VERSION 5.4 ;
NAMESCASESENSITIVE ON ;
BUSBITCHARS "[]" ;
DIVIDERCHAR "/" ;
UNITS
  DATABASE MICRONS 2000 ;
END UNITS
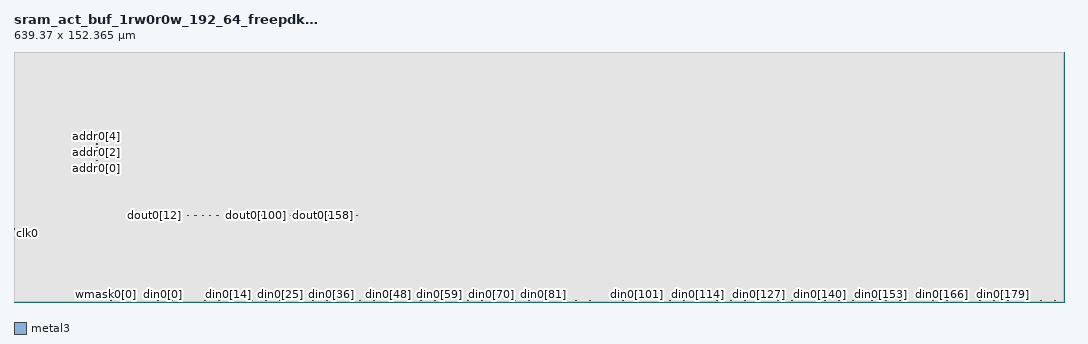
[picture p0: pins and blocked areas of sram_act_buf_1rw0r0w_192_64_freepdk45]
MACRO sram_act_buf_1rw0r0w_192_64_freepdk45
   CLASS BLOCK ;
   SIZE 639.37 BY 152.365 ;
   SYMMETRY X Y R90 ;
   PIN din0[0]
      DIRECTION INPUT ;
      PORT
         LAYER metal3 ;
         RECT  90.465 1.04 90.6 1.175 ;
      END
   END din0[0]
   PIN din0[1]
      DIRECTION INPUT ;
      PORT
         LAYER metal3 ;
         RECT  93.325 1.04 93.46 1.175 ;
      END
   END din0[1]
   PIN din0[2]
      DIRECTION INPUT ;
      PORT
         LAYER metal3 ;
         RECT  96.185 1.04 96.32 1.175 ;
      END
   END din0[2]
   PIN din0[3]
      DIRECTION INPUT ;
      PORT
         LAYER metal3 ;
         RECT  99.045 1.04 99.18 1.175 ;
      END
   END din0[3]
   PIN din0[4]
      DIRECTION INPUT ;
      PORT
         LAYER metal3 ;
         RECT  101.905 1.04 102.04 1.175 ;
      END
   END din0[4]
   PIN din0[5]
      DIRECTION INPUT ;
      PORT
         LAYER metal3 ;
         RECT  104.765 1.04 104.9 1.175 ;
      END
   END din0[5]
   PIN din0[6]
      DIRECTION INPUT ;
      PORT
         LAYER metal3 ;
         RECT  107.625 1.04 107.76 1.175 ;
      END
   END din0[6]
   PIN din0[7]
      DIRECTION INPUT ;
      PORT
         LAYER metal3 ;
         RECT  110.485 1.04 110.62 1.175 ;
      END
   END din0[7]
   PIN din0[8]
      DIRECTION INPUT ;
      PORT
         LAYER metal3 ;
         RECT  113.345 1.04 113.48 1.175 ;
      END
   END din0[8]
   PIN din0[9]
      DIRECTION INPUT ;
      PORT
         LAYER metal3 ;
         RECT  116.205 1.04 116.34 1.175 ;
      END
   END din0[9]
   PIN din0[10]
      DIRECTION INPUT ;
      PORT
         LAYER metal3 ;
         RECT  119.065 1.04 119.2 1.175 ;
      END
   END din0[10]
   PIN din0[11]
      DIRECTION INPUT ;
      PORT
         LAYER metal3 ;
         RECT  121.925 1.04 122.06 1.175 ;
      END
   END din0[11]
   PIN din0[12]
      DIRECTION INPUT ;
      PORT
         LAYER metal3 ;
         RECT  124.785 1.04 124.92 1.175 ;
      END
   END din0[12]
   PIN din0[13]
      DIRECTION INPUT ;
      PORT
         LAYER metal3 ;
         RECT  127.645 1.04 127.78 1.175 ;
      END
   END din0[13]
   PIN din0[14]
      DIRECTION INPUT ;
      PORT
         LAYER metal3 ;
         RECT  130.505 1.04 130.64 1.175 ;
      END
   END din0[14]
   PIN din0[15]
      DIRECTION INPUT ;
      PORT
         LAYER metal3 ;
         RECT  133.365 1.04 133.5 1.175 ;
      END
   END din0[15]
   PIN din0[16]
      DIRECTION INPUT ;
      PORT
         LAYER metal3 ;
         RECT  136.225 1.04 136.36 1.175 ;
      END
   END din0[16]
   PIN din0[17]
      DIRECTION INPUT ;
      PORT
         LAYER metal3 ;
         RECT  139.085 1.04 139.22 1.175 ;
      END
   END din0[17]
   PIN din0[18]
      DIRECTION INPUT ;
      PORT
         LAYER metal3 ;
         RECT  141.945 1.04 142.08 1.175 ;
      END
   END din0[18]
   PIN din0[19]
      DIRECTION INPUT ;
      PORT
         LAYER metal3 ;
         RECT  144.805 1.04 144.94 1.175 ;
      END
   END din0[19]
   PIN din0[20]
      DIRECTION INPUT ;
      PORT
         LAYER metal3 ;
         RECT  147.665 1.04 147.8 1.175 ;
      END
   END din0[20]
   PIN din0[21]
      DIRECTION INPUT ;
      PORT
         LAYER metal3 ;
         RECT  150.525 1.04 150.66 1.175 ;
      END
   END din0[21]
   PIN din0[22]
      DIRECTION INPUT ;
      PORT
         LAYER metal3 ;
         RECT  153.385 1.04 153.52 1.175 ;
      END
   END din0[22]
   PIN din0[23]
      DIRECTION INPUT ;
      PORT
         LAYER metal3 ;
         RECT  156.245 1.04 156.38 1.175 ;
      END
   END din0[23]
   PIN din0[24]
      DIRECTION INPUT ;
      PORT
         LAYER metal3 ;
         RECT  159.105 1.04 159.24 1.175 ;
      END
   END din0[24]
   PIN din0[25]
      DIRECTION INPUT ;
      PORT
         LAYER metal3 ;
         RECT  161.965 1.04 162.1 1.175 ;
      END
   END din0[25]
   PIN din0[26]
      DIRECTION INPUT ;
      PORT
         LAYER metal3 ;
         RECT  164.825 1.04 164.96 1.175 ;
      END
   END din0[26]
   PIN din0[27]
      DIRECTION INPUT ;
      PORT
         LAYER metal3 ;
         RECT  167.685 1.04 167.82 1.175 ;
      END
   END din0[27]
   PIN din0[28]
      DIRECTION INPUT ;
      PORT
         LAYER metal3 ;
         RECT  170.545 1.04 170.68 1.175 ;
      END
   END din0[28]
   PIN din0[29]
      DIRECTION INPUT ;
      PORT
         LAYER metal3 ;
         RECT  173.405 1.04 173.54 1.175 ;
      END
   END din0[29]
   PIN din0[30]
      DIRECTION INPUT ;
      PORT
         LAYER metal3 ;
         RECT  176.265 1.04 176.4 1.175 ;
      END
   END din0[30]
   PIN din0[31]
      DIRECTION INPUT ;
      PORT
         LAYER metal3 ;
         RECT  179.125 1.04 179.26 1.175 ;
      END
   END din0[31]
   PIN din0[32]
      DIRECTION INPUT ;
      PORT
         LAYER metal3 ;
         RECT  181.985 1.04 182.12 1.175 ;
      END
   END din0[32]
   PIN din0[33]
      DIRECTION INPUT ;
      PORT
         LAYER metal3 ;
         RECT  184.845 1.04 184.98 1.175 ;
      END
   END din0[33]
   PIN din0[34]
      DIRECTION INPUT ;
      PORT
         LAYER metal3 ;
         RECT  187.705 1.04 187.84 1.175 ;
      END
   END din0[34]
   PIN din0[35]
      DIRECTION INPUT ;
      PORT
         LAYER metal3 ;
         RECT  190.565 1.04 190.7 1.175 ;
      END
   END din0[35]
   PIN din0[36]
      DIRECTION INPUT ;
      PORT
         LAYER metal3 ;
         RECT  193.425 1.04 193.56 1.175 ;
      END
   END din0[36]
   PIN din0[37]
      DIRECTION INPUT ;
      PORT
         LAYER metal3 ;
         RECT  196.285 1.04 196.42 1.175 ;
      END
   END din0[37]
   PIN din0[38]
      DIRECTION INPUT ;
      PORT
         LAYER metal3 ;
         RECT  199.145 1.04 199.28 1.175 ;
      END
   END din0[38]
   PIN din0[39]
      DIRECTION INPUT ;
      PORT
         LAYER metal3 ;
         RECT  202.005 1.04 202.14 1.175 ;
      END
   END din0[39]
   PIN din0[40]
      DIRECTION INPUT ;
      PORT
         LAYER metal3 ;
         RECT  204.865 1.04 205 1.175 ;
      END
   END din0[40]
   PIN din0[41]
      DIRECTION INPUT ;
      PORT
         LAYER metal3 ;
         RECT  207.725 1.04 207.86 1.175 ;
      END
   END din0[41]
   PIN din0[42]
      DIRECTION INPUT ;
      PORT
         LAYER metal3 ;
         RECT  210.585 1.04 210.72 1.175 ;
      END
   END din0[42]
   PIN din0[43]
      DIRECTION INPUT ;
      PORT
         LAYER metal3 ;
         RECT  213.445 1.04 213.58 1.175 ;
      END
   END din0[43]
   PIN din0[44]
      DIRECTION INPUT ;
      PORT
         LAYER metal3 ;
         RECT  216.305 1.04 216.44 1.175 ;
      END
   END din0[44]
   PIN din0[45]
      DIRECTION INPUT ;
      PORT
         LAYER metal3 ;
         RECT  219.165 1.04 219.3 1.175 ;
      END
   END din0[45]
   PIN din0[46]
      DIRECTION INPUT ;
      PORT
         LAYER metal3 ;
         RECT  222.025 1.04 222.16 1.175 ;
      END
   END din0[46]
   PIN din0[47]
      DIRECTION INPUT ;
      PORT
         LAYER metal3 ;
         RECT  224.885 1.04 225.02 1.175 ;
      END
   END din0[47]
   PIN din0[48]
      DIRECTION INPUT ;
      PORT
         LAYER metal3 ;
         RECT  227.745 1.04 227.88 1.175 ;
      END
   END din0[48]
   PIN din0[49]
      DIRECTION INPUT ;
      PORT
         LAYER metal3 ;
         RECT  230.605 1.04 230.74 1.175 ;
      END
   END din0[49]
   PIN din0[50]
      DIRECTION INPUT ;
      PORT
         LAYER metal3 ;
         RECT  233.465 1.04 233.6 1.175 ;
      END
   END din0[50]
   PIN din0[51]
      DIRECTION INPUT ;
      PORT
         LAYER metal3 ;
         RECT  236.325 1.04 236.46 1.175 ;
      END
   END din0[51]
   PIN din0[52]
      DIRECTION INPUT ;
      PORT
         LAYER metal3 ;
         RECT  239.185 1.04 239.32 1.175 ;
      END
   END din0[52]
   PIN din0[53]
      DIRECTION INPUT ;
      PORT
         LAYER metal3 ;
         RECT  242.045 1.04 242.18 1.175 ;
      END
   END din0[53]
   PIN din0[54]
      DIRECTION INPUT ;
      PORT
         LAYER metal3 ;
         RECT  244.905 1.04 245.04 1.175 ;
      END
   END din0[54]
   PIN din0[55]
      DIRECTION INPUT ;
      PORT
         LAYER metal3 ;
         RECT  247.765 1.04 247.9 1.175 ;
      END
   END din0[55]
   PIN din0[56]
      DIRECTION INPUT ;
      PORT
         LAYER metal3 ;
         RECT  250.625 1.04 250.76 1.175 ;
      END
   END din0[56]
   PIN din0[57]
      DIRECTION INPUT ;
      PORT
         LAYER metal3 ;
         RECT  253.485 1.04 253.62 1.175 ;
      END
   END din0[57]
   PIN din0[58]
      DIRECTION INPUT ;
      PORT
         LAYER metal3 ;
         RECT  256.345 1.04 256.48 1.175 ;
      END
   END din0[58]
   PIN din0[59]
      DIRECTION INPUT ;
      PORT
         LAYER metal3 ;
         RECT  259.205 1.04 259.34 1.175 ;
      END
   END din0[59]
   PIN din0[60]
      DIRECTION INPUT ;
      PORT
         LAYER metal3 ;
         RECT  262.065 1.04 262.2 1.175 ;
      END
   END din0[60]
   PIN din0[61]
      DIRECTION INPUT ;
      PORT
         LAYER metal3 ;
         RECT  264.925 1.04 265.06 1.175 ;
      END
   END din0[61]
   PIN din0[62]
      DIRECTION INPUT ;
      PORT
         LAYER metal3 ;
         RECT  267.785 1.04 267.92 1.175 ;
      END
   END din0[62]
   PIN din0[63]
      DIRECTION INPUT ;
      PORT
         LAYER metal3 ;
         RECT  270.645 1.04 270.78 1.175 ;
      END
   END din0[63]
   PIN din0[64]
      DIRECTION INPUT ;
      PORT
         LAYER metal3 ;
         RECT  273.505 1.04 273.64 1.175 ;
      END
   END din0[64]
   PIN din0[65]
      DIRECTION INPUT ;
      PORT
         LAYER metal3 ;
         RECT  276.365 1.04 276.5 1.175 ;
      END
   END din0[65]
   PIN din0[66]
      DIRECTION INPUT ;
      PORT
         LAYER metal3 ;
         RECT  279.225 1.04 279.36 1.175 ;
      END
   END din0[66]
   PIN din0[67]
      DIRECTION INPUT ;
      PORT
         LAYER metal3 ;
         RECT  282.085 1.04 282.22 1.175 ;
      END
   END din0[67]
   PIN din0[68]
      DIRECTION INPUT ;
      PORT
         LAYER metal3 ;
         RECT  284.945 1.04 285.08 1.175 ;
      END
   END din0[68]
   PIN din0[69]
      DIRECTION INPUT ;
      PORT
         LAYER metal3 ;
         RECT  287.805 1.04 287.94 1.175 ;
      END
   END din0[69]
   PIN din0[70]
      DIRECTION INPUT ;
      PORT
         LAYER metal3 ;
         RECT  290.665 1.04 290.8 1.175 ;
      END
   END din0[70]
   PIN din0[71]
      DIRECTION INPUT ;
      PORT
         LAYER metal3 ;
         RECT  293.525 1.04 293.66 1.175 ;
      END
   END din0[71]
   PIN din0[72]
      DIRECTION INPUT ;
      PORT
         LAYER metal3 ;
         RECT  296.385 1.04 296.52 1.175 ;
      END
   END din0[72]
   PIN din0[73]
      DIRECTION INPUT ;
      PORT
         LAYER metal3 ;
         RECT  299.245 1.04 299.38 1.175 ;
      END
   END din0[73]
   PIN din0[74]
      DIRECTION INPUT ;
      PORT
         LAYER metal3 ;
         RECT  302.105 1.04 302.24 1.175 ;
      END
   END din0[74]
   PIN din0[75]
      DIRECTION INPUT ;
      PORT
         LAYER metal3 ;
         RECT  304.965 1.04 305.1 1.175 ;
      END
   END din0[75]
   PIN din0[76]
      DIRECTION INPUT ;
      PORT
         LAYER metal3 ;
         RECT  307.825 1.04 307.96 1.175 ;
      END
   END din0[76]
   PIN din0[77]
      DIRECTION INPUT ;
      PORT
         LAYER metal3 ;
         RECT  310.685 1.04 310.82 1.175 ;
      END
   END din0[77]
   PIN din0[78]
      DIRECTION INPUT ;
      PORT
         LAYER metal3 ;
         RECT  313.545 1.04 313.68 1.175 ;
      END
   END din0[78]
   PIN din0[79]
      DIRECTION INPUT ;
      PORT
         LAYER metal3 ;
         RECT  316.405 1.04 316.54 1.175 ;
      END
   END din0[79]
   PIN din0[80]
      DIRECTION INPUT ;
      PORT
         LAYER metal3 ;
         RECT  319.265 1.04 319.4 1.175 ;
      END
   END din0[80]
   PIN din0[81]
      DIRECTION INPUT ;
      PORT
         LAYER metal3 ;
         RECT  322.125 1.04 322.26 1.175 ;
      END
   END din0[81]
   PIN din0[82]
      DIRECTION INPUT ;
      PORT
         LAYER metal3 ;
         RECT  324.985 1.04 325.12 1.175 ;
      END
   END din0[82]
   PIN din0[83]
      DIRECTION INPUT ;
      PORT
         LAYER metal3 ;
         RECT  327.845 1.04 327.98 1.175 ;
      END
   END din0[83]
   PIN din0[84]
      DIRECTION INPUT ;
      PORT
         LAYER metal3 ;
         RECT  330.705 1.04 330.84 1.175 ;
      END
   END din0[84]
   PIN din0[85]
      DIRECTION INPUT ;
      PORT
         LAYER metal3 ;
         RECT  333.565 1.04 333.7 1.175 ;
      END
   END din0[85]
   PIN din0[86]
      DIRECTION INPUT ;
      PORT
         LAYER metal3 ;
         RECT  336.425 1.04 336.56 1.175 ;
      END
   END din0[86]
   PIN din0[87]
      DIRECTION INPUT ;
      PORT
         LAYER metal3 ;
         RECT  339.285 1.04 339.42 1.175 ;
      END
   END din0[87]
   PIN din0[88]
      DIRECTION INPUT ;
      PORT
         LAYER metal3 ;
         RECT  342.145 1.04 342.28 1.175 ;
      END
   END din0[88]
   PIN din0[89]
      DIRECTION INPUT ;
      PORT
         LAYER metal3 ;
         RECT  345.005 1.04 345.14 1.175 ;
      END
   END din0[89]
   PIN din0[90]
      DIRECTION INPUT ;
      PORT
         LAYER metal3 ;
         RECT  347.865 1.04 348 1.175 ;
      END
   END din0[90]
   PIN din0[91]
      DIRECTION INPUT ;
      PORT
         LAYER metal3 ;
         RECT  350.725 1.04 350.86 1.175 ;
      END
   END din0[91]
   PIN din0[92]
      DIRECTION INPUT ;
      PORT
         LAYER metal3 ;
         RECT  353.585 1.04 353.72 1.175 ;
      END
   END din0[92]
   PIN din0[93]
      DIRECTION INPUT ;
      PORT
         LAYER metal3 ;
         RECT  356.445 1.04 356.58 1.175 ;
      END
   END din0[93]
   PIN din0[94]
      DIRECTION INPUT ;
      PORT
         LAYER metal3 ;
         RECT  359.305 1.04 359.44 1.175 ;
      END
   END din0[94]
   PIN din0[95]
      DIRECTION INPUT ;
      PORT
         LAYER metal3 ;
         RECT  362.165 1.04 362.3 1.175 ;
      END
   END din0[95]
   PIN din0[96]
      DIRECTION INPUT ;
      PORT
         LAYER metal3 ;
         RECT  365.025 1.04 365.16 1.175 ;
      END
   END din0[96]
   PIN din0[97]
      DIRECTION INPUT ;
      PORT
         LAYER metal3 ;
         RECT  367.885 1.04 368.02 1.175 ;
      END
   END din0[97]
   PIN din0[98]
      DIRECTION INPUT ;
      PORT
         LAYER metal3 ;
         RECT  370.745 1.04 370.88 1.175 ;
      END
   END din0[98]
   PIN din0[99]
      DIRECTION INPUT ;
      PORT
         LAYER metal3 ;
         RECT  373.605 1.04 373.74 1.175 ;
      END
   END din0[99]
   PIN din0[100]
      DIRECTION INPUT ;
      PORT
         LAYER metal3 ;
         RECT  376.465 1.04 376.6 1.175 ;
      END
   END din0[100]
   PIN din0[101]
      DIRECTION INPUT ;
      PORT
         LAYER metal3 ;
         RECT  379.325 1.04 379.46 1.175 ;
      END
   END din0[101]
   PIN din0[102]
      DIRECTION INPUT ;
      PORT
         LAYER metal3 ;
         RECT  382.185 1.04 382.32 1.175 ;
      END
   END din0[102]
   PIN din0[103]
      DIRECTION INPUT ;
      PORT
         LAYER metal3 ;
         RECT  385.045 1.04 385.18 1.175 ;
      END
   END din0[103]
   PIN din0[104]
      DIRECTION INPUT ;
      PORT
         LAYER metal3 ;
         RECT  387.905 1.04 388.04 1.175 ;
      END
   END din0[104]
   PIN din0[105]
      DIRECTION INPUT ;
      PORT
         LAYER metal3 ;
         RECT  390.765 1.04 390.9 1.175 ;
      END
   END din0[105]
   PIN din0[106]
      DIRECTION INPUT ;
      PORT
         LAYER metal3 ;
         RECT  393.625 1.04 393.76 1.175 ;
      END
   END din0[106]
   PIN din0[107]
      DIRECTION INPUT ;
      PORT
         LAYER metal3 ;
         RECT  396.485 1.04 396.62 1.175 ;
      END
   END din0[107]
   PIN din0[108]
      DIRECTION INPUT ;
      PORT
         LAYER metal3 ;
         RECT  399.345 1.04 399.48 1.175 ;
      END
   END din0[108]
   PIN din0[109]
      DIRECTION INPUT ;
      PORT
         LAYER metal3 ;
         RECT  402.205 1.04 402.34 1.175 ;
      END
   END din0[109]
   PIN din0[110]
      DIRECTION INPUT ;
      PORT
         LAYER metal3 ;
         RECT  405.065 1.04 405.2 1.175 ;
      END
   END din0[110]
   PIN din0[111]
      DIRECTION INPUT ;
      PORT
         LAYER metal3 ;
         RECT  407.925 1.04 408.06 1.175 ;
      END
   END din0[111]
   PIN din0[112]
      DIRECTION INPUT ;
      PORT
         LAYER metal3 ;
         RECT  410.785 1.04 410.92 1.175 ;
      END
   END din0[112]
   PIN din0[113]
      DIRECTION INPUT ;
      PORT
         LAYER metal3 ;
         RECT  413.645 1.04 413.78 1.175 ;
      END
   END din0[113]
   PIN din0[114]
      DIRECTION INPUT ;
      PORT
         LAYER metal3 ;
         RECT  416.505 1.04 416.64 1.175 ;
      END
   END din0[114]
   PIN din0[115]
      DIRECTION INPUT ;
      PORT
         LAYER metal3 ;
         RECT  419.365 1.04 419.5 1.175 ;
      END
   END din0[115]
   PIN din0[116]
      DIRECTION INPUT ;
      PORT
         LAYER metal3 ;
         RECT  422.225 1.04 422.36 1.175 ;
      END
   END din0[116]
   PIN din0[117]
      DIRECTION INPUT ;
      PORT
         LAYER metal3 ;
         RECT  425.085 1.04 425.22 1.175 ;
      END
   END din0[117]
   PIN din0[118]
      DIRECTION INPUT ;
      PORT
         LAYER metal3 ;
         RECT  427.945 1.04 428.08 1.175 ;
      END
   END din0[118]
   PIN din0[119]
      DIRECTION INPUT ;
      PORT
         LAYER metal3 ;
         RECT  430.805 1.04 430.94 1.175 ;
      END
   END din0[119]
   PIN din0[120]
      DIRECTION INPUT ;
      PORT
         LAYER metal3 ;
         RECT  433.665 1.04 433.8 1.175 ;
      END
   END din0[120]
   PIN din0[121]
      DIRECTION INPUT ;
      PORT
         LAYER metal3 ;
         RECT  436.525 1.04 436.66 1.175 ;
      END
   END din0[121]
   PIN din0[122]
      DIRECTION INPUT ;
      PORT
         LAYER metal3 ;
         RECT  439.385 1.04 439.52 1.175 ;
      END
   END din0[122]
   PIN din0[123]
      DIRECTION INPUT ;
      PORT
         LAYER metal3 ;
         RECT  442.245 1.04 442.38 1.175 ;
      END
   END din0[123]
   PIN din0[124]
      DIRECTION INPUT ;
      PORT
         LAYER metal3 ;
         RECT  445.105 1.04 445.24 1.175 ;
      END
   END din0[124]
   PIN din0[125]
      DIRECTION INPUT ;
      PORT
         LAYER metal3 ;
         RECT  447.965 1.04 448.1 1.175 ;
      END
   END din0[125]
   PIN din0[126]
      DIRECTION INPUT ;
      PORT
         LAYER metal3 ;
         RECT  450.825 1.04 450.96 1.175 ;
      END
   END din0[126]
   PIN din0[127]
      DIRECTION INPUT ;
      PORT
         LAYER metal3 ;
         RECT  453.685 1.04 453.82 1.175 ;
      END
   END din0[127]
   PIN din0[128]
      DIRECTION INPUT ;
      PORT
         LAYER metal3 ;
         RECT  456.545 1.04 456.68 1.175 ;
      END
   END din0[128]
   PIN din0[129]
      DIRECTION INPUT ;
      PORT
         LAYER metal3 ;
         RECT  459.405 1.04 459.54 1.175 ;
      END
   END din0[129]
   PIN din0[130]
      DIRECTION INPUT ;
      PORT
         LAYER metal3 ;
         RECT  462.265 1.04 462.4 1.175 ;
      END
   END din0[130]
   PIN din0[131]
      DIRECTION INPUT ;
      PORT
         LAYER metal3 ;
         RECT  465.125 1.04 465.26 1.175 ;
      END
   END din0[131]
   PIN din0[132]
      DIRECTION INPUT ;
      PORT
         LAYER metal3 ;
         RECT  467.985 1.04 468.12 1.175 ;
      END
   END din0[132]
   PIN din0[133]
      DIRECTION INPUT ;
      PORT
         LAYER metal3 ;
         RECT  470.845 1.04 470.98 1.175 ;
      END
   END din0[133]
   PIN din0[134]
      DIRECTION INPUT ;
      PORT
         LAYER metal3 ;
         RECT  473.705 1.04 473.84 1.175 ;
      END
   END din0[134]
   PIN din0[135]
      DIRECTION INPUT ;
      PORT
         LAYER metal3 ;
         RECT  476.565 1.04 476.7 1.175 ;
      END
   END din0[135]
   PIN din0[136]
      DIRECTION INPUT ;
      PORT
         LAYER metal3 ;
         RECT  479.425 1.04 479.56 1.175 ;
      END
   END din0[136]
   PIN din0[137]
      DIRECTION INPUT ;
      PORT
         LAYER metal3 ;
         RECT  482.285 1.04 482.42 1.175 ;
      END
   END din0[137]
   PIN din0[138]
      DIRECTION INPUT ;
      PORT
         LAYER metal3 ;
         RECT  485.145 1.04 485.28 1.175 ;
      END
   END din0[138]
   PIN din0[139]
      DIRECTION INPUT ;
      PORT
         LAYER metal3 ;
         RECT  488.005 1.04 488.14 1.175 ;
      END
   END din0[139]
   PIN din0[140]
      DIRECTION INPUT ;
      PORT
         LAYER metal3 ;
         RECT  490.865 1.04 491 1.175 ;
      END
   END din0[140]
   PIN din0[141]
      DIRECTION INPUT ;
      PORT
         LAYER metal3 ;
         RECT  493.725 1.04 493.86 1.175 ;
      END
   END din0[141]
   PIN din0[142]
      DIRECTION INPUT ;
      PORT
         LAYER metal3 ;
         RECT  496.585 1.04 496.72 1.175 ;
      END
   END din0[142]
   PIN din0[143]
      DIRECTION INPUT ;
      PORT
         LAYER metal3 ;
         RECT  499.445 1.04 499.58 1.175 ;
      END
   END din0[143]
   PIN din0[144]
      DIRECTION INPUT ;
      PORT
         LAYER metal3 ;
         RECT  502.305 1.04 502.44 1.175 ;
      END
   END din0[144]
   PIN din0[145]
      DIRECTION INPUT ;
      PORT
         LAYER metal3 ;
         RECT  505.165 1.04 505.3 1.175 ;
      END
   END din0[145]
   PIN din0[146]
      DIRECTION INPUT ;
      PORT
         LAYER metal3 ;
         RECT  508.025 1.04 508.16 1.175 ;
      END
   END din0[146]
   PIN din0[147]
      DIRECTION INPUT ;
      PORT
         LAYER metal3 ;
         RECT  510.885 1.04 511.02 1.175 ;
      END
   END din0[147]
   PIN din0[148]
      DIRECTION INPUT ;
      PORT
         LAYER metal3 ;
         RECT  513.745 1.04 513.88 1.175 ;
      END
   END din0[148]
   PIN din0[149]
      DIRECTION INPUT ;
      PORT
         LAYER metal3 ;
         RECT  516.605 1.04 516.74 1.175 ;
      END
   END din0[149]
   PIN din0[150]
      DIRECTION INPUT ;
      PORT
         LAYER metal3 ;
         RECT  519.465 1.04 519.6 1.175 ;
      END
   END din0[150]
   PIN din0[151]
      DIRECTION INPUT ;
      PORT
         LAYER metal3 ;
         RECT  522.325 1.04 522.46 1.175 ;
      END
   END din0[151]
   PIN din0[152]
      DIRECTION INPUT ;
      PORT
         LAYER metal3 ;
         RECT  525.185 1.04 525.32 1.175 ;
      END
   END din0[152]
   PIN din0[153]
      DIRECTION INPUT ;
      PORT
         LAYER metal3 ;
         RECT  528.045 1.04 528.18 1.175 ;
      END
   END din0[153]
   PIN din0[154]
      DIRECTION INPUT ;
      PORT
         LAYER metal3 ;
         RECT  530.905 1.04 531.04 1.175 ;
      END
   END din0[154]
   PIN din0[155]
      DIRECTION INPUT ;
      PORT
         LAYER metal3 ;
         RECT  533.765 1.04 533.9 1.175 ;
      END
   END din0[155]
   PIN din0[156]
      DIRECTION INPUT ;
      PORT
         LAYER metal3 ;
         RECT  536.625 1.04 536.76 1.175 ;
      END
   END din0[156]
   PIN din0[157]
      DIRECTION INPUT ;
      PORT
         LAYER metal3 ;
         RECT  539.485 1.04 539.62 1.175 ;
      END
   END din0[157]
   PIN din0[158]
      DIRECTION INPUT ;
      PORT
         LAYER metal3 ;
         RECT  542.345 1.04 542.48 1.175 ;
      END
   END din0[158]
   PIN din0[159]
      DIRECTION INPUT ;
      PORT
         LAYER metal3 ;
         RECT  545.205 1.04 545.34 1.175 ;
      END
   END din0[159]
   PIN din0[160]
      DIRECTION INPUT ;
      PORT
         LAYER metal3 ;
         RECT  548.065 1.04 548.2 1.175 ;
      END
   END din0[160]
   PIN din0[161]
      DIRECTION INPUT ;
      PORT
         LAYER metal3 ;
         RECT  550.925 1.04 551.06 1.175 ;
      END
   END din0[161]
   PIN din0[162]
      DIRECTION INPUT ;
      PORT
         LAYER metal3 ;
         RECT  553.785 1.04 553.92 1.175 ;
      END
   END din0[162]
   PIN din0[163]
      DIRECTION INPUT ;
      PORT
         LAYER metal3 ;
         RECT  556.645 1.04 556.78 1.175 ;
      END
   END din0[163]
   PIN din0[164]
      DIRECTION INPUT ;
      PORT
         LAYER metal3 ;
         RECT  559.505 1.04 559.64 1.175 ;
      END
   END din0[164]
   PIN din0[165]
      DIRECTION INPUT ;
      PORT
         LAYER metal3 ;
         RECT  562.365 1.04 562.5 1.175 ;
      END
   END din0[165]
   PIN din0[166]
      DIRECTION INPUT ;
      PORT
         LAYER metal3 ;
         RECT  565.225 1.04 565.36 1.175 ;
      END
   END din0[166]
   PIN din0[167]
      DIRECTION INPUT ;
      PORT
         LAYER metal3 ;
         RECT  568.085 1.04 568.22 1.175 ;
      END
   END din0[167]
   PIN din0[168]
      DIRECTION INPUT ;
      PORT
         LAYER metal3 ;
         RECT  570.945 1.04 571.08 1.175 ;
      END
   END din0[168]
   PIN din0[169]
      DIRECTION INPUT ;
      PORT
         LAYER metal3 ;
         RECT  573.805 1.04 573.94 1.175 ;
      END
   END din0[169]
   PIN din0[170]
      DIRECTION INPUT ;
      PORT
         LAYER metal3 ;
         RECT  576.665 1.04 576.8 1.175 ;
      END
   END din0[170]
   PIN din0[171]
      DIRECTION INPUT ;
      PORT
         LAYER metal3 ;
         RECT  579.525 1.04 579.66 1.175 ;
      END
   END din0[171]
   PIN din0[172]
      DIRECTION INPUT ;
      PORT
         LAYER metal3 ;
         RECT  582.385 1.04 582.52 1.175 ;
      END
   END din0[172]
   PIN din0[173]
      DIRECTION INPUT ;
      PORT
         LAYER metal3 ;
         RECT  585.245 1.04 585.38 1.175 ;
      END
   END din0[173]
   PIN din0[174]
      DIRECTION INPUT ;
      PORT
         LAYER metal3 ;
         RECT  588.105 1.04 588.24 1.175 ;
      END
   END din0[174]
   PIN din0[175]
      DIRECTION INPUT ;
      PORT
         LAYER metal3 ;
         RECT  590.965 1.04 591.1 1.175 ;
      END
   END din0[175]
   PIN din0[176]
      DIRECTION INPUT ;
      PORT
         LAYER metal3 ;
         RECT  593.825 1.04 593.96 1.175 ;
      END
   END din0[176]
   PIN din0[177]
      DIRECTION INPUT ;
      PORT
         LAYER metal3 ;
         RECT  596.685 1.04 596.82 1.175 ;
      END
   END din0[177]
   PIN din0[178]
      DIRECTION INPUT ;
      PORT
         LAYER metal3 ;
         RECT  599.545 1.04 599.68 1.175 ;
      END
   END din0[178]
   PIN din0[179]
      DIRECTION INPUT ;
      PORT
         LAYER metal3 ;
         RECT  602.405 1.04 602.54 1.175 ;
      END
   END din0[179]
   PIN din0[180]
      DIRECTION INPUT ;
      PORT
         LAYER metal3 ;
         RECT  605.265 1.04 605.4 1.175 ;
      END
   END din0[180]
   PIN din0[181]
      DIRECTION INPUT ;
      PORT
         LAYER metal3 ;
         RECT  608.125 1.04 608.26 1.175 ;
      END
   END din0[181]
   PIN din0[182]
      DIRECTION INPUT ;
      PORT
         LAYER metal3 ;
         RECT  610.985 1.04 611.12 1.175 ;
      END
   END din0[182]
   PIN din0[183]
      DIRECTION INPUT ;
      PORT
         LAYER metal3 ;
         RECT  613.845 1.04 613.98 1.175 ;
      END
   END din0[183]
   PIN din0[184]
      DIRECTION INPUT ;
      PORT
         LAYER metal3 ;
         RECT  616.705 1.04 616.84 1.175 ;
      END
   END din0[184]
   PIN din0[185]
      DIRECTION INPUT ;
      PORT
         LAYER metal3 ;
         RECT  619.565 1.04 619.7 1.175 ;
      END
   END din0[185]
   PIN din0[186]
      DIRECTION INPUT ;
      PORT
         LAYER metal3 ;
         RECT  622.425 1.04 622.56 1.175 ;
      END
   END din0[186]
   PIN din0[187]
      DIRECTION INPUT ;
      PORT
         LAYER metal3 ;
         RECT  625.285 1.04 625.42 1.175 ;
      END
   END din0[187]
   PIN din0[188]
      DIRECTION INPUT ;
      PORT
         LAYER metal3 ;
         RECT  628.145 1.04 628.28 1.175 ;
      END
   END din0[188]
   PIN din0[189]
      DIRECTION INPUT ;
      PORT
         LAYER metal3 ;
         RECT  631.005 1.04 631.14 1.175 ;
      END
   END din0[189]
   PIN din0[190]
      DIRECTION INPUT ;
      PORT
         LAYER metal3 ;
         RECT  633.865 1.04 634 1.175 ;
      END
   END din0[190]
   PIN din0[191]
      DIRECTION INPUT ;
      PORT
         LAYER metal3 ;
         RECT  636.725 1.04 636.86 1.175 ;
      END
   END din0[191]
   PIN addr0[0]
      DIRECTION INPUT ;
      PORT
         LAYER metal3 ;
         RECT  50.425 86.32 50.56 86.455 ;
      END
   END addr0[0]
   PIN addr0[1]
      DIRECTION INPUT ;
      PORT
         LAYER metal3 ;
         RECT  50.425 89.05 50.56 89.185 ;
      END
   END addr0[1]
   PIN addr0[2]
      DIRECTION INPUT ;
      PORT
         LAYER metal3 ;
         RECT  50.425 91.26 50.56 91.395 ;
      END
   END addr0[2]
   PIN addr0[3]
      DIRECTION INPUT ;
      PORT
         LAYER metal3 ;
         RECT  50.425 93.99 50.56 94.125 ;
      END
   END addr0[3]
   PIN addr0[4]
      DIRECTION INPUT ;
      PORT
         LAYER metal3 ;
         RECT  50.425 96.2 50.56 96.335 ;
      END
   END addr0[4]
   PIN addr0[5]
      DIRECTION INPUT ;
      PORT
         LAYER metal3 ;
         RECT  50.425 98.93 50.56 99.065 ;
      END
   END addr0[5]
   PIN csb0
      DIRECTION INPUT ;
      PORT
         LAYER metal3 ;
         RECT  0.285 41.6 0.42 41.735 ;
      END
   END csb0
   PIN web0
      DIRECTION INPUT ;
      PORT
         LAYER metal3 ;
         RECT  0.285 44.33 0.42 44.465 ;
      END
   END web0
   PIN clk0
      DIRECTION INPUT ;
      PORT
         LAYER metal3 ;
         RECT  6.53 41.685 6.66 41.82 ;
      END
   END clk0
   PIN wmask0[0]
      DIRECTION INPUT ;
      PORT
         LAYER metal3 ;
         RECT  56.145 1.04 56.28 1.175 ;
      END
   END wmask0[0]
   PIN wmask0[1]
      DIRECTION INPUT ;
      PORT
         LAYER metal3 ;
         RECT  59.005 1.04 59.14 1.175 ;
      END
   END wmask0[1]
   PIN wmask0[2]
      DIRECTION INPUT ;
      PORT
         LAYER metal3 ;
         RECT  61.865 1.04 62 1.175 ;
      END
   END wmask0[2]
   PIN wmask0[3]
      DIRECTION INPUT ;
      PORT
         LAYER metal3 ;
         RECT  64.725 1.04 64.86 1.175 ;
      END
   END wmask0[3]
   PIN wmask0[4]
      DIRECTION INPUT ;
      PORT
         LAYER metal3 ;
         RECT  67.585 1.04 67.72 1.175 ;
      END
   END wmask0[4]
   PIN wmask0[5]
      DIRECTION INPUT ;
      PORT
         LAYER metal3 ;
         RECT  70.445 1.04 70.58 1.175 ;
      END
   END wmask0[5]
   PIN wmask0[6]
      DIRECTION INPUT ;
      PORT
         LAYER metal3 ;
         RECT  73.305 1.04 73.44 1.175 ;
      END
   END wmask0[6]
   PIN wmask0[7]
      DIRECTION INPUT ;
      PORT
         LAYER metal3 ;
         RECT  76.165 1.04 76.3 1.175 ;
      END
   END wmask0[7]
   PIN wmask0[8]
      DIRECTION INPUT ;
      PORT
         LAYER metal3 ;
         RECT  79.025 1.04 79.16 1.175 ;
      END
   END wmask0[8]
   PIN wmask0[9]
      DIRECTION INPUT ;
      PORT
         LAYER metal3 ;
         RECT  81.885 1.04 82.02 1.175 ;
      END
   END wmask0[9]
   PIN wmask0[10]
      DIRECTION INPUT ;
      PORT
         LAYER metal3 ;
         RECT  84.745 1.04 84.88 1.175 ;
      END
   END wmask0[10]
   PIN wmask0[11]
      DIRECTION INPUT ;
      PORT
         LAYER metal3 ;
         RECT  87.605 1.04 87.74 1.175 ;
      END
   END wmask0[11]
   PIN dout0[0]
      DIRECTION OUTPUT ;
      PORT
         LAYER metal3 ;
         RECT  76.955 52.74 77.09 52.88 ;
      END
   END dout0[0]
   PIN dout0[1]
      DIRECTION OUTPUT ;
      PORT
         LAYER metal3 ;
         RECT  77.66 52.74 77.795 52.88 ;
      END
   END dout0[1]
   PIN dout0[2]
      DIRECTION OUTPUT ;
      PORT
         LAYER metal3 ;
         RECT  78.365 52.74 78.5 52.88 ;
      END
   END dout0[2]
   PIN dout0[3]
      DIRECTION OUTPUT ;
      PORT
         LAYER metal3 ;
         RECT  79.07 52.74 79.205 52.88 ;
      END
   END dout0[3]
   PIN dout0[4]
      DIRECTION OUTPUT ;
      PORT
         LAYER metal3 ;
         RECT  79.775 52.74 79.91 52.88 ;
      END
   END dout0[4]
   PIN dout0[5]
      DIRECTION OUTPUT ;
      PORT
         LAYER metal3 ;
         RECT  80.48 52.74 80.615 52.88 ;
      END
   END dout0[5]
   PIN dout0[6]
      DIRECTION OUTPUT ;
      PORT
         LAYER metal3 ;
         RECT  81.185 52.74 81.32 52.88 ;
      END
   END dout0[6]
   PIN dout0[7]
      DIRECTION OUTPUT ;
      PORT
         LAYER metal3 ;
         RECT  81.89 52.74 82.025 52.88 ;
      END
   END dout0[7]
   PIN dout0[8]
      DIRECTION OUTPUT ;
      PORT
         LAYER metal3 ;
         RECT  82.595 52.74 82.73 52.88 ;
      END
   END dout0[8]
   PIN dout0[9]
      DIRECTION OUTPUT ;
      PORT
         LAYER metal3 ;
         RECT  83.3 52.74 83.435 52.88 ;
      END
   END dout0[9]
   PIN dout0[10]
      DIRECTION OUTPUT ;
      PORT
         LAYER metal3 ;
         RECT  84.005 52.74 84.14 52.88 ;
      END
   END dout0[10]
   PIN dout0[11]
      DIRECTION OUTPUT ;
      PORT
         LAYER metal3 ;
         RECT  84.71 52.74 84.845 52.88 ;
      END
   END dout0[11]
   PIN dout0[12]
      DIRECTION OUTPUT ;
      PORT
         LAYER metal3 ;
         RECT  85.415 52.74 85.55 52.88 ;
      END
   END dout0[12]
   PIN dout0[13]
      DIRECTION OUTPUT ;
      PORT
         LAYER metal3 ;
         RECT  86.12 52.74 86.255 52.88 ;
      END
   END dout0[13]
   PIN dout0[14]
      DIRECTION OUTPUT ;
      PORT
         LAYER metal3 ;
         RECT  86.825 52.74 86.96 52.88 ;
      END
   END dout0[14]
   PIN dout0[15]
      DIRECTION OUTPUT ;
      PORT
         LAYER metal3 ;
         RECT  87.53 52.74 87.665 52.88 ;
      END
   END dout0[15]
   PIN dout0[16]
      DIRECTION OUTPUT ;
      PORT
         LAYER metal3 ;
         RECT  88.235 52.74 88.37 52.88 ;
      END
   END dout0[16]
   PIN dout0[17]
      DIRECTION OUTPUT ;
      PORT
         LAYER metal3 ;
         RECT  88.94 52.74 89.075 52.88 ;
      END
   END dout0[17]
   PIN dout0[18]
      DIRECTION OUTPUT ;
      PORT
         LAYER metal3 ;
         RECT  89.645 52.74 89.78 52.88 ;
      END
   END dout0[18]
   PIN dout0[19]
      DIRECTION OUTPUT ;
      PORT
         LAYER metal3 ;
         RECT  90.35 52.74 90.485 52.88 ;
      END
   END dout0[19]
   PIN dout0[20]
      DIRECTION OUTPUT ;
      PORT
         LAYER metal3 ;
         RECT  91.055 52.74 91.19 52.88 ;
      END
   END dout0[20]
   PIN dout0[21]
      DIRECTION OUTPUT ;
      PORT
         LAYER metal3 ;
         RECT  91.76 52.74 91.895 52.88 ;
      END
   END dout0[21]
   PIN dout0[22]
      DIRECTION OUTPUT ;
      PORT
         LAYER metal3 ;
         RECT  92.465 52.74 92.6 52.88 ;
      END
   END dout0[22]
   PIN dout0[23]
      DIRECTION OUTPUT ;
      PORT
         LAYER metal3 ;
         RECT  93.17 52.74 93.305 52.88 ;
      END
   END dout0[23]
   PIN dout0[24]
      DIRECTION OUTPUT ;
      PORT
         LAYER metal3 ;
         RECT  93.875 52.74 94.01 52.88 ;
      END
   END dout0[24]
   PIN dout0[25]
      DIRECTION OUTPUT ;
      PORT
         LAYER metal3 ;
         RECT  94.58 52.74 94.715 52.88 ;
      END
   END dout0[25]
   PIN dout0[26]
      DIRECTION OUTPUT ;
      PORT
         LAYER metal3 ;
         RECT  95.285 52.74 95.42 52.88 ;
      END
   END dout0[26]
   PIN dout0[27]
      DIRECTION OUTPUT ;
      PORT
         LAYER metal3 ;
         RECT  95.99 52.74 96.125 52.88 ;
      END
   END dout0[27]
   PIN dout0[28]
      DIRECTION OUTPUT ;
      PORT
         LAYER metal3 ;
         RECT  96.695 52.74 96.83 52.88 ;
      END
   END dout0[28]
   PIN dout0[29]
      DIRECTION OUTPUT ;
      PORT
         LAYER metal3 ;
         RECT  97.4 52.74 97.535 52.88 ;
      END
   END dout0[29]
   PIN dout0[30]
      DIRECTION OUTPUT ;
      PORT
         LAYER metal3 ;
         RECT  98.105 52.74 98.24 52.88 ;
      END
   END dout0[30]
   PIN dout0[31]
      DIRECTION OUTPUT ;
      PORT
         LAYER metal3 ;
         RECT  98.81 52.74 98.945 52.88 ;
      END
   END dout0[31]
   PIN dout0[32]
      DIRECTION OUTPUT ;
      PORT
         LAYER metal3 ;
         RECT  99.515 52.74 99.65 52.88 ;
      END
   END dout0[32]
   PIN dout0[33]
      DIRECTION OUTPUT ;
      PORT
         LAYER metal3 ;
         RECT  100.22 52.74 100.355 52.88 ;
      END
   END dout0[33]
   PIN dout0[34]
      DIRECTION OUTPUT ;
      PORT
         LAYER metal3 ;
         RECT  100.925 52.74 101.06 52.88 ;
      END
   END dout0[34]
   PIN dout0[35]
      DIRECTION OUTPUT ;
      PORT
         LAYER metal3 ;
         RECT  101.63 52.74 101.765 52.88 ;
      END
   END dout0[35]
   PIN dout0[36]
      DIRECTION OUTPUT ;
      PORT
         LAYER metal3 ;
         RECT  102.335 52.74 102.47 52.88 ;
      END
   END dout0[36]
   PIN dout0[37]
      DIRECTION OUTPUT ;
      PORT
         LAYER metal3 ;
         RECT  103.04 52.74 103.175 52.88 ;
      END
   END dout0[37]
   PIN dout0[38]
      DIRECTION OUTPUT ;
      PORT
         LAYER metal3 ;
         RECT  103.745 52.74 103.88 52.88 ;
      END
   END dout0[38]
   PIN dout0[39]
      DIRECTION OUTPUT ;
      PORT
         LAYER metal3 ;
         RECT  104.45 52.74 104.585 52.88 ;
      END
   END dout0[39]
   PIN dout0[40]
      DIRECTION OUTPUT ;
      PORT
         LAYER metal3 ;
         RECT  105.155 52.74 105.29 52.88 ;
      END
   END dout0[40]
   PIN dout0[41]
      DIRECTION OUTPUT ;
      PORT
         LAYER metal3 ;
         RECT  105.86 52.74 105.995 52.88 ;
      END
   END dout0[41]
   PIN dout0[42]
      DIRECTION OUTPUT ;
      PORT
         LAYER metal3 ;
         RECT  106.565 52.74 106.7 52.88 ;
      END
   END dout0[42]
   PIN dout0[43]
      DIRECTION OUTPUT ;
      PORT
         LAYER metal3 ;
         RECT  107.27 52.74 107.405 52.88 ;
      END
   END dout0[43]
   PIN dout0[44]
      DIRECTION OUTPUT ;
      PORT
         LAYER metal3 ;
         RECT  107.975 52.74 108.11 52.88 ;
      END
   END dout0[44]
   PIN dout0[45]
      DIRECTION OUTPUT ;
      PORT
         LAYER metal3 ;
         RECT  108.68 52.74 108.815 52.88 ;
      END
   END dout0[45]
   PIN dout0[46]
      DIRECTION OUTPUT ;
      PORT
         LAYER metal3 ;
         RECT  109.385 52.74 109.52 52.88 ;
      END
   END dout0[46]
   PIN dout0[47]
      DIRECTION OUTPUT ;
      PORT
         LAYER metal3 ;
         RECT  110.09 52.74 110.225 52.88 ;
      END
   END dout0[47]
   PIN dout0[48]
      DIRECTION OUTPUT ;
      PORT
         LAYER metal3 ;
         RECT  110.795 52.74 110.93 52.88 ;
      END
   END dout0[48]
   PIN dout0[49]
      DIRECTION OUTPUT ;
      PORT
         LAYER metal3 ;
         RECT  111.5 52.74 111.635 52.88 ;
      END
   END dout0[49]
   PIN dout0[50]
      DIRECTION OUTPUT ;
      PORT
         LAYER metal3 ;
         RECT  112.205 52.74 112.34 52.88 ;
      END
   END dout0[50]
   PIN dout0[51]
      DIRECTION OUTPUT ;
      PORT
         LAYER metal3 ;
         RECT  112.91 52.74 113.045 52.88 ;
      END
   END dout0[51]
   PIN dout0[52]
      DIRECTION OUTPUT ;
      PORT
         LAYER metal3 ;
         RECT  113.615 52.74 113.75 52.88 ;
      END
   END dout0[52]
   PIN dout0[53]
      DIRECTION OUTPUT ;
      PORT
         LAYER metal3 ;
         RECT  114.32 52.74 114.455 52.88 ;
      END
   END dout0[53]
   PIN dout0[54]
      DIRECTION OUTPUT ;
      PORT
         LAYER metal3 ;
         RECT  115.025 52.74 115.16 52.88 ;
      END
   END dout0[54]
   PIN dout0[55]
      DIRECTION OUTPUT ;
      PORT
         LAYER metal3 ;
         RECT  115.73 52.74 115.865 52.88 ;
      END
   END dout0[55]
   PIN dout0[56]
      DIRECTION OUTPUT ;
      PORT
         LAYER metal3 ;
         RECT  116.435 52.74 116.57 52.88 ;
      END
   END dout0[56]
   PIN dout0[57]
      DIRECTION OUTPUT ;
      PORT
         LAYER metal3 ;
         RECT  117.14 52.74 117.275 52.88 ;
      END
   END dout0[57]
   PIN dout0[58]
      DIRECTION OUTPUT ;
      PORT
         LAYER metal3 ;
         RECT  117.845 52.74 117.98 52.88 ;
      END
   END dout0[58]
   PIN dout0[59]
      DIRECTION OUTPUT ;
      PORT
         LAYER metal3 ;
         RECT  118.55 52.74 118.685 52.88 ;
      END
   END dout0[59]
   PIN dout0[60]
      DIRECTION OUTPUT ;
      PORT
         LAYER metal3 ;
         RECT  119.255 52.74 119.39 52.88 ;
      END
   END dout0[60]
   PIN dout0[61]
      DIRECTION OUTPUT ;
      PORT
         LAYER metal3 ;
         RECT  119.96 52.74 120.095 52.88 ;
      END
   END dout0[61]
   PIN dout0[62]
      DIRECTION OUTPUT ;
      PORT
         LAYER metal3 ;
         RECT  120.665 52.74 120.8 52.88 ;
      END
   END dout0[62]
   PIN dout0[63]
      DIRECTION OUTPUT ;
      PORT
         LAYER metal3 ;
         RECT  121.37 52.74 121.505 52.88 ;
      END
   END dout0[63]
   PIN dout0[64]
      DIRECTION OUTPUT ;
      PORT
         LAYER metal3 ;
         RECT  122.075 52.74 122.21 52.88 ;
      END
   END dout0[64]
   PIN dout0[65]
      DIRECTION OUTPUT ;
      PORT
         LAYER metal3 ;
         RECT  122.78 52.74 122.915 52.88 ;
      END
   END dout0[65]
   PIN dout0[66]
      DIRECTION OUTPUT ;
      PORT
         LAYER metal3 ;
         RECT  123.485 52.74 123.62 52.88 ;
      END
   END dout0[66]
   PIN dout0[67]
      DIRECTION OUTPUT ;
      PORT
         LAYER metal3 ;
         RECT  124.19 52.74 124.325 52.88 ;
      END
   END dout0[67]
   PIN dout0[68]
      DIRECTION OUTPUT ;
      PORT
         LAYER metal3 ;
         RECT  124.895 52.74 125.03 52.88 ;
      END
   END dout0[68]
   PIN dout0[69]
      DIRECTION OUTPUT ;
      PORT
         LAYER metal3 ;
         RECT  125.6 52.74 125.735 52.88 ;
      END
   END dout0[69]
   PIN dout0[70]
      DIRECTION OUTPUT ;
      PORT
         LAYER metal3 ;
         RECT  126.305 52.74 126.44 52.88 ;
      END
   END dout0[70]
   PIN dout0[71]
      DIRECTION OUTPUT ;
      PORT
         LAYER metal3 ;
         RECT  127.01 52.74 127.145 52.88 ;
      END
   END dout0[71]
   PIN dout0[72]
      DIRECTION OUTPUT ;
      PORT
         LAYER metal3 ;
         RECT  127.715 52.74 127.85 52.88 ;
      END
   END dout0[72]
   PIN dout0[73]
      DIRECTION OUTPUT ;
      PORT
         LAYER metal3 ;
         RECT  128.42 52.74 128.555 52.88 ;
      END
   END dout0[73]
   PIN dout0[74]
      DIRECTION OUTPUT ;
      PORT
         LAYER metal3 ;
         RECT  129.125 52.74 129.26 52.88 ;
      END
   END dout0[74]
   PIN dout0[75]
      DIRECTION OUTPUT ;
      PORT
         LAYER metal3 ;
         RECT  129.83 52.74 129.965 52.88 ;
      END
   END dout0[75]
   PIN dout0[76]
      DIRECTION OUTPUT ;
      PORT
         LAYER metal3 ;
         RECT  130.535 52.74 130.67 52.88 ;
      END
   END dout0[76]
   PIN dout0[77]
      DIRECTION OUTPUT ;
      PORT
         LAYER metal3 ;
         RECT  131.24 52.74 131.375 52.88 ;
      END
   END dout0[77]
   PIN dout0[78]
      DIRECTION OUTPUT ;
      PORT
         LAYER metal3 ;
         RECT  131.945 52.74 132.08 52.88 ;
      END
   END dout0[78]
   PIN dout0[79]
      DIRECTION OUTPUT ;
      PORT
         LAYER metal3 ;
         RECT  132.65 52.74 132.785 52.88 ;
      END
   END dout0[79]
   PIN dout0[80]
      DIRECTION OUTPUT ;
      PORT
         LAYER metal3 ;
         RECT  133.355 52.74 133.49 52.88 ;
      END
   END dout0[80]
   PIN dout0[81]
      DIRECTION OUTPUT ;
      PORT
         LAYER metal3 ;
         RECT  134.06 52.74 134.195 52.88 ;
      END
   END dout0[81]
   PIN dout0[82]
      DIRECTION OUTPUT ;
      PORT
         LAYER metal3 ;
         RECT  134.765 52.74 134.9 52.88 ;
      END
   END dout0[82]
   PIN dout0[83]
      DIRECTION OUTPUT ;
      PORT
         LAYER metal3 ;
         RECT  135.47 52.74 135.605 52.88 ;
      END
   END dout0[83]
   PIN dout0[84]
      DIRECTION OUTPUT ;
      PORT
         LAYER metal3 ;
         RECT  136.175 52.74 136.31 52.88 ;
      END
   END dout0[84]
   PIN dout0[85]
      DIRECTION OUTPUT ;
      PORT
         LAYER metal3 ;
         RECT  136.88 52.74 137.015 52.88 ;
      END
   END dout0[85]
   PIN dout0[86]
      DIRECTION OUTPUT ;
      PORT
         LAYER metal3 ;
         RECT  137.585 52.74 137.72 52.88 ;
      END
   END dout0[86]
   PIN dout0[87]
      DIRECTION OUTPUT ;
      PORT
         LAYER metal3 ;
         RECT  138.29 52.74 138.425 52.88 ;
      END
   END dout0[87]
   PIN dout0[88]
      DIRECTION OUTPUT ;
      PORT
         LAYER metal3 ;
         RECT  138.995 52.74 139.13 52.88 ;
      END
   END dout0[88]
   PIN dout0[89]
      DIRECTION OUTPUT ;
      PORT
         LAYER metal3 ;
         RECT  139.7 52.74 139.835 52.88 ;
      END
   END dout0[89]
   PIN dout0[90]
      DIRECTION OUTPUT ;
      PORT
         LAYER metal3 ;
         RECT  140.405 52.74 140.54 52.88 ;
      END
   END dout0[90]
   PIN dout0[91]
      DIRECTION OUTPUT ;
      PORT
         LAYER metal3 ;
         RECT  141.11 52.74 141.245 52.88 ;
      END
   END dout0[91]
   PIN dout0[92]
      DIRECTION OUTPUT ;
      PORT
         LAYER metal3 ;
         RECT  141.815 52.74 141.95 52.88 ;
      END
   END dout0[92]
   PIN dout0[93]
      DIRECTION OUTPUT ;
      PORT
         LAYER metal3 ;
         RECT  142.52 52.74 142.655 52.88 ;
      END
   END dout0[93]
   PIN dout0[94]
      DIRECTION OUTPUT ;
      PORT
         LAYER metal3 ;
         RECT  143.225 52.74 143.36 52.88 ;
      END
   END dout0[94]
   PIN dout0[95]
      DIRECTION OUTPUT ;
      PORT
         LAYER metal3 ;
         RECT  143.93 52.74 144.065 52.88 ;
      END
   END dout0[95]
   PIN dout0[96]
      DIRECTION OUTPUT ;
      PORT
         LAYER metal3 ;
         RECT  144.635 52.74 144.77 52.88 ;
      END
   END dout0[96]
   PIN dout0[97]
      DIRECTION OUTPUT ;
      PORT
         LAYER metal3 ;
         RECT  145.34 52.74 145.475 52.88 ;
      END
   END dout0[97]
   PIN dout0[98]
      DIRECTION OUTPUT ;
      PORT
         LAYER metal3 ;
         RECT  146.045 52.74 146.18 52.88 ;
      END
   END dout0[98]
   PIN dout0[99]
      DIRECTION OUTPUT ;
      PORT
         LAYER metal3 ;
         RECT  146.75 52.74 146.885 52.88 ;
      END
   END dout0[99]
   PIN dout0[100]
      DIRECTION OUTPUT ;
      PORT
         LAYER metal3 ;
         RECT  147.455 52.74 147.59 52.88 ;
      END
   END dout0[100]
   PIN dout0[101]
      DIRECTION OUTPUT ;
      PORT
         LAYER metal3 ;
         RECT  148.16 52.74 148.295 52.88 ;
      END
   END dout0[101]
   PIN dout0[102]
      DIRECTION OUTPUT ;
      PORT
         LAYER metal3 ;
         RECT  148.865 52.74 149 52.88 ;
      END
   END dout0[102]
   PIN dout0[103]
      DIRECTION OUTPUT ;
      PORT
         LAYER metal3 ;
         RECT  149.57 52.74 149.705 52.88 ;
      END
   END dout0[103]
   PIN dout0[104]
      DIRECTION OUTPUT ;
      PORT
         LAYER metal3 ;
         RECT  150.275 52.74 150.41 52.88 ;
      END
   END dout0[104]
   PIN dout0[105]
      DIRECTION OUTPUT ;
      PORT
         LAYER metal3 ;
         RECT  150.98 52.74 151.115 52.88 ;
      END
   END dout0[105]
   PIN dout0[106]
      DIRECTION OUTPUT ;
      PORT
         LAYER metal3 ;
         RECT  151.685 52.74 151.82 52.88 ;
      END
   END dout0[106]
   PIN dout0[107]
      DIRECTION OUTPUT ;
      PORT
         LAYER metal3 ;
         RECT  152.39 52.74 152.525 52.88 ;
      END
   END dout0[107]
   PIN dout0[108]
      DIRECTION OUTPUT ;
      PORT
         LAYER metal3 ;
         RECT  153.095 52.74 153.23 52.88 ;
      END
   END dout0[108]
   PIN dout0[109]
      DIRECTION OUTPUT ;
      PORT
         LAYER metal3 ;
         RECT  153.8 52.74 153.935 52.88 ;
      END
   END dout0[109]
   PIN dout0[110]
      DIRECTION OUTPUT ;
      PORT
         LAYER metal3 ;
         RECT  154.505 52.74 154.64 52.88 ;
      END
   END dout0[110]
   PIN dout0[111]
      DIRECTION OUTPUT ;
      PORT
         LAYER metal3 ;
         RECT  155.21 52.74 155.345 52.88 ;
      END
   END dout0[111]
   PIN dout0[112]
      DIRECTION OUTPUT ;
      PORT
         LAYER metal3 ;
         RECT  155.915 52.74 156.05 52.88 ;
      END
   END dout0[112]
   PIN dout0[113]
      DIRECTION OUTPUT ;
      PORT
         LAYER metal3 ;
         RECT  156.62 52.74 156.755 52.88 ;
      END
   END dout0[113]
   PIN dout0[114]
      DIRECTION OUTPUT ;
      PORT
         LAYER metal3 ;
         RECT  157.325 52.74 157.46 52.88 ;
      END
   END dout0[114]
   PIN dout0[115]
      DIRECTION OUTPUT ;
      PORT
         LAYER metal3 ;
         RECT  158.03 52.74 158.165 52.88 ;
      END
   END dout0[115]
   PIN dout0[116]
      DIRECTION OUTPUT ;
      PORT
         LAYER metal3 ;
         RECT  158.735 52.74 158.87 52.88 ;
      END
   END dout0[116]
   PIN dout0[117]
      DIRECTION OUTPUT ;
      PORT
         LAYER metal3 ;
         RECT  159.44 52.74 159.575 52.88 ;
      END
   END dout0[117]
   PIN dout0[118]
      DIRECTION OUTPUT ;
      PORT
         LAYER metal3 ;
         RECT  160.145 52.74 160.28 52.88 ;
      END
   END dout0[118]
   PIN dout0[119]
      DIRECTION OUTPUT ;
      PORT
         LAYER metal3 ;
         RECT  160.85 52.74 160.985 52.88 ;
      END
   END dout0[119]
   PIN dout0[120]
      DIRECTION OUTPUT ;
      PORT
         LAYER metal3 ;
         RECT  161.555 52.74 161.69 52.88 ;
      END
   END dout0[120]
   PIN dout0[121]
      DIRECTION OUTPUT ;
      PORT
         LAYER metal3 ;
         RECT  162.26 52.74 162.395 52.88 ;
      END
   END dout0[121]
   PIN dout0[122]
      DIRECTION OUTPUT ;
      PORT
         LAYER metal3 ;
         RECT  162.965 52.74 163.1 52.88 ;
      END
   END dout0[122]
   PIN dout0[123]
      DIRECTION OUTPUT ;
      PORT
         LAYER metal3 ;
         RECT  163.67 52.74 163.805 52.88 ;
      END
   END dout0[123]
   PIN dout0[124]
      DIRECTION OUTPUT ;
      PORT
         LAYER metal3 ;
         RECT  164.375 52.74 164.51 52.88 ;
      END
   END dout0[124]
   PIN dout0[125]
      DIRECTION OUTPUT ;
      PORT
         LAYER metal3 ;
         RECT  165.08 52.74 165.215 52.88 ;
      END
   END dout0[125]
   PIN dout0[126]
      DIRECTION OUTPUT ;
      PORT
         LAYER metal3 ;
         RECT  165.785 52.74 165.92 52.88 ;
      END
   END dout0[126]
   PIN dout0[127]
      DIRECTION OUTPUT ;
      PORT
         LAYER metal3 ;
         RECT  166.49 52.74 166.625 52.88 ;
      END
   END dout0[127]
   PIN dout0[128]
      DIRECTION OUTPUT ;
      PORT
         LAYER metal3 ;
         RECT  167.195 52.74 167.33 52.88 ;
      END
   END dout0[128]
   PIN dout0[129]
      DIRECTION OUTPUT ;
      PORT
         LAYER metal3 ;
         RECT  167.9 52.74 168.035 52.88 ;
      END
   END dout0[129]
   PIN dout0[130]
      DIRECTION OUTPUT ;
      PORT
         LAYER metal3 ;
         RECT  168.605 52.74 168.74 52.88 ;
      END
   END dout0[130]
   PIN dout0[131]
      DIRECTION OUTPUT ;
      PORT
         LAYER metal3 ;
         RECT  169.31 52.74 169.445 52.88 ;
      END
   END dout0[131]
   PIN dout0[132]
      DIRECTION OUTPUT ;
      PORT
         LAYER metal3 ;
         RECT  170.015 52.74 170.15 52.88 ;
      END
   END dout0[132]
   PIN dout0[133]
      DIRECTION OUTPUT ;
      PORT
         LAYER metal3 ;
         RECT  170.72 52.74 170.855 52.88 ;
      END
   END dout0[133]
   PIN dout0[134]
      DIRECTION OUTPUT ;
      PORT
         LAYER metal3 ;
         RECT  171.425 52.74 171.56 52.88 ;
      END
   END dout0[134]
   PIN dout0[135]
      DIRECTION OUTPUT ;
      PORT
         LAYER metal3 ;
         RECT  172.13 52.74 172.265 52.88 ;
      END
   END dout0[135]
   PIN dout0[136]
      DIRECTION OUTPUT ;
      PORT
         LAYER metal3 ;
         RECT  172.835 52.74 172.97 52.88 ;
      END
   END dout0[136]
   PIN dout0[137]
      DIRECTION OUTPUT ;
      PORT
         LAYER metal3 ;
         RECT  173.54 52.74 173.675 52.88 ;
      END
   END dout0[137]
   PIN dout0[138]
      DIRECTION OUTPUT ;
      PORT
         LAYER metal3 ;
         RECT  174.245 52.74 174.38 52.88 ;
      END
   END dout0[138]
   PIN dout0[139]
      DIRECTION OUTPUT ;
      PORT
         LAYER metal3 ;
         RECT  174.95 52.74 175.085 52.88 ;
      END
   END dout0[139]
   PIN dout0[140]
      DIRECTION OUTPUT ;
      PORT
         LAYER metal3 ;
         RECT  175.655 52.74 175.79 52.88 ;
      END
   END dout0[140]
   PIN dout0[141]
      DIRECTION OUTPUT ;
      PORT
         LAYER metal3 ;
         RECT  176.36 52.74 176.495 52.88 ;
      END
   END dout0[141]
   PIN dout0[142]
      DIRECTION OUTPUT ;
      PORT
         LAYER metal3 ;
         RECT  177.065 52.74 177.2 52.88 ;
      END
   END dout0[142]
   PIN dout0[143]
      DIRECTION OUTPUT ;
      PORT
         LAYER metal3 ;
         RECT  177.77 52.74 177.905 52.88 ;
      END
   END dout0[143]
   PIN dout0[144]
      DIRECTION OUTPUT ;
      PORT
         LAYER metal3 ;
         RECT  178.475 52.74 178.61 52.88 ;
      END
   END dout0[144]
   PIN dout0[145]
      DIRECTION OUTPUT ;
      PORT
         LAYER metal3 ;
         RECT  179.18 52.74 179.315 52.88 ;
      END
   END dout0[145]
   PIN dout0[146]
      DIRECTION OUTPUT ;
      PORT
         LAYER metal3 ;
         RECT  179.885 52.74 180.02 52.88 ;
      END
   END dout0[146]
   PIN dout0[147]
      DIRECTION OUTPUT ;
      PORT
         LAYER metal3 ;
         RECT  180.59 52.74 180.725 52.88 ;
      END
   END dout0[147]
   PIN dout0[148]
      DIRECTION OUTPUT ;
      PORT
         LAYER metal3 ;
         RECT  181.295 52.74 181.43 52.88 ;
      END
   END dout0[148]
   PIN dout0[149]
      DIRECTION OUTPUT ;
      PORT
         LAYER metal3 ;
         RECT  182 52.74 182.135 52.88 ;
      END
   END dout0[149]
   PIN dout0[150]
      DIRECTION OUTPUT ;
      PORT
         LAYER metal3 ;
         RECT  182.705 52.74 182.84 52.88 ;
      END
   END dout0[150]
   PIN dout0[151]
      DIRECTION OUTPUT ;
      PORT
         LAYER metal3 ;
         RECT  183.41 52.74 183.545 52.88 ;
      END
   END dout0[151]
   PIN dout0[152]
      DIRECTION OUTPUT ;
      PORT
         LAYER metal3 ;
         RECT  184.115 52.74 184.25 52.88 ;
      END
   END dout0[152]
   PIN dout0[153]
      DIRECTION OUTPUT ;
      PORT
         LAYER metal3 ;
         RECT  184.82 52.74 184.955 52.88 ;
      END
   END dout0[153]
   PIN dout0[154]
      DIRECTION OUTPUT ;
      PORT
         LAYER metal3 ;
         RECT  185.525 52.74 185.66 52.88 ;
      END
   END dout0[154]
   PIN dout0[155]
      DIRECTION OUTPUT ;
      PORT
         LAYER metal3 ;
         RECT  186.23 52.74 186.365 52.88 ;
      END
   END dout0[155]
   PIN dout0[156]
      DIRECTION OUTPUT ;
      PORT
         LAYER metal3 ;
         RECT  186.935 52.74 187.07 52.88 ;
      END
   END dout0[156]
   PIN dout0[157]
      DIRECTION OUTPUT ;
      PORT
         LAYER metal3 ;
         RECT  187.64 52.74 187.775 52.88 ;
      END
   END dout0[157]
   PIN dout0[158]
      DIRECTION OUTPUT ;
      PORT
         LAYER metal3 ;
         RECT  188.345 52.74 188.48 52.88 ;
      END
   END dout0[158]
   PIN dout0[159]
      DIRECTION OUTPUT ;
      PORT
         LAYER metal3 ;
         RECT  189.05 52.74 189.185 52.88 ;
      END
   END dout0[159]
   PIN dout0[160]
      DIRECTION OUTPUT ;
      PORT
         LAYER metal3 ;
         RECT  189.755 52.74 189.89 52.88 ;
      END
   END dout0[160]
   PIN dout0[161]
      DIRECTION OUTPUT ;
      PORT
         LAYER metal3 ;
         RECT  190.46 52.74 190.595 52.88 ;
      END
   END dout0[161]
   PIN dout0[162]
      DIRECTION OUTPUT ;
      PORT
         LAYER metal3 ;
         RECT  191.165 52.74 191.3 52.88 ;
      END
   END dout0[162]
   PIN dout0[163]
      DIRECTION OUTPUT ;
      PORT
         LAYER metal3 ;
         RECT  191.87 52.74 192.005 52.88 ;
      END
   END dout0[163]
   PIN dout0[164]
      DIRECTION OUTPUT ;
      PORT
         LAYER metal3 ;
         RECT  192.575 52.74 192.71 52.88 ;
      END
   END dout0[164]
   PIN dout0[165]
      DIRECTION OUTPUT ;
      PORT
         LAYER metal3 ;
         RECT  193.28 52.74 193.415 52.88 ;
      END
   END dout0[165]
   PIN dout0[166]
      DIRECTION OUTPUT ;
      PORT
         LAYER metal3 ;
         RECT  193.985 52.74 194.12 52.88 ;
      END
   END dout0[166]
   PIN dout0[167]
      DIRECTION OUTPUT ;
      PORT
         LAYER metal3 ;
         RECT  194.69 52.74 194.825 52.88 ;
      END
   END dout0[167]
   PIN dout0[168]
      DIRECTION OUTPUT ;
      PORT
         LAYER metal3 ;
         RECT  195.395 52.74 195.53 52.88 ;
      END
   END dout0[168]
   PIN dout0[169]
      DIRECTION OUTPUT ;
      PORT
         LAYER metal3 ;
         RECT  196.1 52.74 196.235 52.88 ;
      END
   END dout0[169]
   PIN dout0[170]
      DIRECTION OUTPUT ;
      PORT
         LAYER metal3 ;
         RECT  196.805 52.74 196.94 52.88 ;
      END
   END dout0[170]
   PIN dout0[171]
      DIRECTION OUTPUT ;
      PORT
         LAYER metal3 ;
         RECT  197.51 52.74 197.645 52.88 ;
      END
   END dout0[171]
   PIN dout0[172]
      DIRECTION OUTPUT ;
      PORT
         LAYER metal3 ;
         RECT  198.215 52.74 198.35 52.88 ;
      END
   END dout0[172]
   PIN dout0[173]
      DIRECTION OUTPUT ;
      PORT
         LAYER metal3 ;
         RECT  198.92 52.74 199.055 52.88 ;
      END
   END dout0[173]
   PIN dout0[174]
      DIRECTION OUTPUT ;
      PORT
         LAYER metal3 ;
         RECT  199.625 52.74 199.76 52.88 ;
      END
   END dout0[174]
   PIN dout0[175]
      DIRECTION OUTPUT ;
      PORT
         LAYER metal3 ;
         RECT  200.33 52.74 200.465 52.88 ;
      END
   END dout0[175]
   PIN dout0[176]
      DIRECTION OUTPUT ;
      PORT
         LAYER metal3 ;
         RECT  201.035 52.74 201.17 52.88 ;
      END
   END dout0[176]
   PIN dout0[177]
      DIRECTION OUTPUT ;
      PORT
         LAYER metal3 ;
         RECT  201.74 52.74 201.875 52.88 ;
      END
   END dout0[177]
   PIN dout0[178]
      DIRECTION OUTPUT ;
      PORT
         LAYER metal3 ;
         RECT  202.445 52.74 202.58 52.88 ;
      END
   END dout0[178]
   PIN dout0[179]
      DIRECTION OUTPUT ;
      PORT
         LAYER metal3 ;
         RECT  203.15 52.74 203.285 52.88 ;
      END
   END dout0[179]
   PIN dout0[180]
      DIRECTION OUTPUT ;
      PORT
         LAYER metal3 ;
         RECT  203.855 52.74 203.99 52.88 ;
      END
   END dout0[180]
   PIN dout0[181]
      DIRECTION OUTPUT ;
      PORT
         LAYER metal3 ;
         RECT  204.56 52.74 204.695 52.88 ;
      END
   END dout0[181]
   PIN dout0[182]
      DIRECTION OUTPUT ;
      PORT
         LAYER metal3 ;
         RECT  205.265 52.74 205.4 52.88 ;
      END
   END dout0[182]
   PIN dout0[183]
      DIRECTION OUTPUT ;
      PORT
         LAYER metal3 ;
         RECT  205.97 52.74 206.105 52.88 ;
      END
   END dout0[183]
   PIN dout0[184]
      DIRECTION OUTPUT ;
      PORT
         LAYER metal3 ;
         RECT  206.675 52.74 206.81 52.88 ;
      END
   END dout0[184]
   PIN dout0[185]
      DIRECTION OUTPUT ;
      PORT
         LAYER metal3 ;
         RECT  207.38 52.74 207.515 52.88 ;
      END
   END dout0[185]
   PIN dout0[186]
      DIRECTION OUTPUT ;
      PORT
         LAYER metal3 ;
         RECT  208.085 52.74 208.22 52.88 ;
      END
   END dout0[186]
   PIN dout0[187]
      DIRECTION OUTPUT ;
      PORT
         LAYER metal3 ;
         RECT  208.79 52.74 208.925 52.88 ;
      END
   END dout0[187]
   PIN dout0[188]
      DIRECTION OUTPUT ;
      PORT
         LAYER metal3 ;
         RECT  209.495 52.74 209.63 52.88 ;
      END
   END dout0[188]
   PIN dout0[189]
      DIRECTION OUTPUT ;
      PORT
         LAYER metal3 ;
         RECT  210.2 52.74 210.335 52.88 ;
      END
   END dout0[189]
   PIN dout0[190]
      DIRECTION OUTPUT ;
      PORT
         LAYER metal3 ;
         RECT  210.905 52.74 211.04 52.88 ;
      END
   END dout0[190]
   PIN dout0[191]
      DIRECTION OUTPUT ;
      PORT
         LAYER metal3 ;
         RECT  211.61 52.74 211.745 52.88 ;
      END
   END dout0[191]
   PIN vdd
      DIRECTION INOUT ;
      USE POWER ; 
      SHAPE ABUTMENT ; 
      PORT
      END
   END vdd
   PIN gnd
      DIRECTION INOUT ;
      USE GROUND ; 
      SHAPE ABUTMENT ; 
      PORT
      END
   END gnd
   OBS
   LAYER  metal1 ;
      RECT  0.14 0.14 639.23 152.225 ;
   LAYER  metal2 ;
      RECT  0.14 0.14 639.23 152.225 ;
   END
END    sram_act_buf_1rw0r0w_192_64_freepdk45
END    LIBRARY
